VERSION 5.7 ;
  NOWIREEXTENSIONATPIN ON ;
  DIVIDERCHAR "/" ;
  BUSBITCHARS "[]" ;
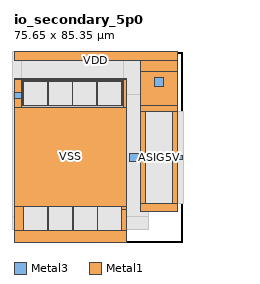
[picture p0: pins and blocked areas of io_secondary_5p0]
MACRO io_secondary_5p0
  CLASS BLOCK ;
  FOREIGN io_secondary_5p0 ;
  ORIGIN 0.000 0.000 ;
  SIZE 75.650 BY 85.350 ;
  PIN ASIG5V
    DIRECTION INPUT ;
    PORT
      LAYER Metal3 ;
      RECT 74.025 37.225 75.525 38.725 ;
    END
  END ASIG5V
  PIN to_gate
    DIRECTION OUTPUT ;
    ANTENNADIFFAREA 800.000000 ;
    PORT
      LAYER Metal3 ;
      RECT 51.800 35.975 55.800 39.975 ;
    END
  END to_gate
  PIN VDD
    DIRECTION INOUT ;
    USE POWER ;
    PORT
      LAYER Metal1 ;
        RECT 0.000 81.400 73.600 85.350 ;
        RECT 56.700 81.390 73.600 81.400 ;
        RECT 56.850 76.650 73.600 81.390 ;
        RECT 3.900 72.700 4.150 72.750 ;
        RECT 48.450 72.700 48.700 72.750 ;
        RECT 3.900 72.250 48.700 72.700 ;
        RECT 3.900 72.200 4.235 72.250 ;
        RECT 4.005 61.435 4.235 72.200 ;
        RECT 15.085 61.435 15.315 72.250 ;
        RECT 26.165 61.435 26.395 72.250 ;
        RECT 37.245 61.435 37.475 72.250 ;
        RECT 48.325 72.200 48.700 72.250 ;
        RECT 48.325 61.435 48.555 72.200 ;
        RECT 4.005 61.205 48.555 61.435 ;
        RECT 56.800 61.200 73.600 76.650 ;
        RECT 56.850 58.550 73.600 61.200 ;
        RECT 56.850 17.450 59.150 58.550 ;
        RECT 71.350 17.450 73.600 58.550 ;
        RECT 56.850 13.800 73.600 17.450 ;
      LAYER Metal3 ;
        RECT 63.200 69.950 67.200 73.950 ;
    END
  END VDD
  PIN VSS
    DIRECTION INOUT ;
    USE GROUND ;
    PORT
      LAYER Metal1 ;
        RECT 0.000 73.395 3.450 73.400 ;
        RECT 49.100 73.395 50.750 73.400 ;
        RECT 0.000 73.165 50.750 73.395 ;
        RECT 0.000 60.600 3.450 73.165 ;
        RECT 49.100 60.600 50.750 73.165 ;
        RECT 0.000 16.045 50.750 60.600 ;
        RECT 0.000 5.115 4.215 16.045 ;
        RECT 15.145 5.115 15.375 16.045 ;
        RECT 26.305 5.115 26.535 16.045 ;
        RECT 37.465 5.115 37.695 16.045 ;
        RECT 48.500 15.900 50.750 16.045 ;
        RECT 48.500 14.750 50.760 15.900 ;
        RECT 48.510 5.115 50.760 14.750 ;
        RECT 0.000 0.000 50.760 5.115 ;
      LAYER Metal3 ;
        RECT 0.225 64.325 3.225 67.325 ;
    END
  END VSS
  OBS
      LAYER Via1 ;
        RECT 69.910 17.460 76.140 58.490 ;
        RECT -0.265 63.835 3.715 67.815 ;
        RECT 62.710 69.460 67.690 74.440 ;
        RECT -0.490 5.415 60.540 85.590 ;
      LAYER Via2 ;
        RECT 69.910 17.460 76.140 58.490 ;
        RECT -0.490 11.510 60.540 66.290 ;
        RECT -0.265 63.835 3.715 67.815 ;
        RECT 62.710 69.460 67.690 74.440 ;
        RECT 3.310 71.660 49.190 85.590 ;
      LAYER Metal1 ;
        RECT 4.460 5.415 14.900 15.745 ;
        RECT 15.620 5.415 26.060 15.745 ;
        RECT 26.780 5.415 37.220 15.745 ;
        RECT 37.940 5.415 48.380 15.745 ;
        RECT 59.170 17.720 60.280 58.230 ;
        RECT 70.170 17.720 71.280 58.230 ;
        RECT 4.440 61.695 14.880 72.025 ;
        RECT 15.520 61.695 25.960 72.025 ;
        RECT 26.600 61.695 37.040 72.025 ;
        RECT 37.680 61.695 48.120 72.025 ;
      LAYER Metal2 ;
        RECT 69.910 17.460 76.140 58.490 ;
        RECT -0.490 11.510 60.540 66.290 ;
        RECT -0.265 63.835 3.715 67.815 ;
        RECT 62.710 69.460 67.690 74.440 ;
        RECT 3.310 71.660 49.190 85.590 ;
      LAYER Nwell ;
        RECT 3.780 60.980 48.780 72.740 ;
        RECT 58.650 16.900 71.830 59.060 ;
      LAYER Pwell ;
        RECT 2.900 72.740 49.660 73.620 ;
        RECT 2.900 60.980 3.780 72.740 ;
        RECT 48.780 60.980 49.660 72.740 ;
        RECT 2.900 60.100 49.660 60.980 ;
        RECT 3.800 4.700 49.040 16.460 ;
  END
END io_secondary_5p0
